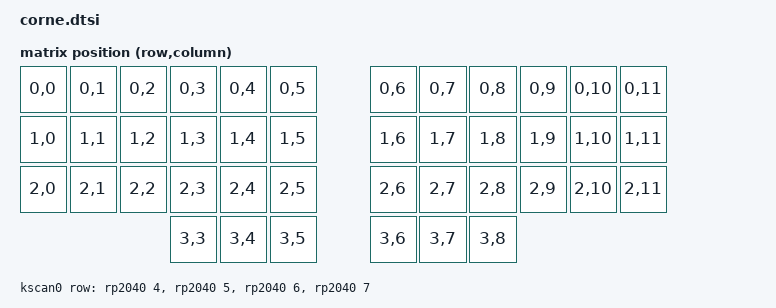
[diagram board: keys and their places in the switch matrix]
/*
 * Copyright (c) 2020 Pete Johanson
 *
 * SPDX-License-Identifier: MIT
 */
#include <dt-bindings/led/led.h>
#include <dt-bindings/zmk/matrix_transform.h>
#include "corne-layouts.dtsi"
/ {
	chosen {
		zephyr,display = &oled;
		zmk,kscan = &kscan0;
		zmk,physical-layout = &layout_0;
	};

	default_transform: keymap_transform_0 {
		compatible = "zmk,matrix-transform";
		columns = <12>;
		rows = <4>;
// | SW1  | SW2  | SW3  | SW4  | SW5  | SW6  |   | SW6  | SW5  | SW4  | SW3  | SW2  | SW1  |
// | SW7  | SW8  | SW9  | SW10 | SW11 | SW12 |   | SW12 | SW11 | SW10 | SW9  | SW8  | SW7  |
// | SW13 | SW14 | SW15 | SW16 | SW17 | SW18 |   | SW18 | SW17 | SW16 | SW15 | SW14 | SW13 |
//                      | SW19 | SW20 | SW21 |   | SW21 | SW20 | SW19 |
		map = <
RC(0,0) RC(0,1) RC(0,2) RC(0,3) RC(0,4) RC(0,5)  RC(0,6)  RC(0,7) RC(0,8) RC(0,9) RC(0,10) RC(0,11)
RC(1,0) RC(1,1) RC(1,2) RC(1,3) RC(1,4) RC(1,5)  RC(1,6)  RC(1,7) RC(1,8) RC(1,9) RC(1,10) RC(1,11)
RC(2,0) RC(2,1) RC(2,2) RC(2,3) RC(2,4) RC(2,5)  RC(2,6)  RC(2,7) RC(2,8) RC(2,9) RC(2,10) RC(2,11)
                        RC(3,3) RC(3,4) RC(3,5)  RC(3,6) RC(3,7) RC(3,8)
		>;
	};

	 kscan0: kscan {
        compatible = "zmk,kscan-gpio-matrix";
        label = "KSCAN";

        wakeup-source;
        diode-direction = "col2row";
		/* Rows: originally defined for ProMicro/nRF (&pro_micro). For RP2040
		   we map to &rp2040 with the same numeric GPIO indices by default.
		   Adjust if your board uses different pin numbering. */
		row-gpios = <&rp2040 4 (GPIO_ACTIVE_HIGH | GPIO_PULL_DOWN)>
			, <&rp2040 5 (GPIO_ACTIVE_HIGH | GPIO_PULL_DOWN)>
			, <&rp2040 6 (GPIO_ACTIVE_HIGH | GPIO_PULL_DOWN)>
			, <&rp2040 7 (GPIO_ACTIVE_HIGH | GPIO_PULL_DOWN)>;
    };
};

/* I2C / pinctrl: the original file used NRF_PSEL macros which are nRF-specific
   and will break RP2040 builds. Commenting original nRF pinctrl entries and
   providing an RP2040-friendly example below. */

/*
&pinctrl {
       i2c0_default: i2c0_default {
               group1 {
                       psels = <NRF_PSEL(TWIM_SDA, 0, 17)>,
                               <NRF_PSEL(TWIM_SCL, 0, 20)>;
               };
       };

       i2c0_sleep: i2c0_sleep {
               group1 {
                       psels = <NRF_PSEL(TWIM_SDA, 0, 17)>,
                               <NRF_PSEL(TWIM_SCL, 0, 20)>;
                       low-power-enable;
               };
       };
};
*/

/* RP2040 example: enable i2c0 and attach ssd1306. Update SDA/SCL GPIO numbers
   to match your board (common examples: SDA=26, SCL=27 on some RP2040 boards). */
&i2c0 {
    status = "okay";

    oled: ssd1306@3c {
        compatible = "solomon,ssd1306fb";
        reg = <0x3c>;
        width = <128>;
        height = <32>;
    };
};

/* Original ProMicro/nRF I2C node commented for reference:
&pro_micro_i2c {
    status = "okay";

    oled: ssd1306@3c {
        compatible = "solomon,ssd1306fb";
        reg = <0x3c>;
        width = <128>;
        height = <32>;
        segment-offset = <0>;
        page-offset = <0>;
        display-offset = <0>;
        multiplex-ratio = <31>;
        segment-remap;
        com-invdir;
        com-sequential;
        inversion-on;
        prechargep = <0x22>;
    };
};
*/

/* SPI / WS2812: original file used Nordic SPIM and NRF_PSEL macros; comment
   out the nRF-specific config. On RP2040, WS2812 is commonly driven via PIO
   or a dedicated driver; adapt below as needed. */

/*
&pinctrl {
    spi3_default: spi3_default {
        group1 {
            psels = <NRF_PSEL(SPIM_MOSI, 0, 6)>;
        };
    };

    spi3_sleep: spi3_sleep {
        group1 {
            psels = <NRF_PSEL(SPIM_MOSI, 0, 6)>;
            low-power-enable;
		};
	};
};

&spi3 {
	compatible = "nordic,nrf-spim";
	status = "okay";

	pinctrl-0 = <&spi3_default>;
	pinctrl-1 = <&spi3_sleep>;
	pinctrl-names = "default", "sleep";

	led_strip: ws2812@0 {
		compatible = "worldsemi,ws2812-spi";
		label = "WS2812";

		/* SPI */
		reg = <0>; /* ignored, but necessary for SPI bindings */
		spi-max-frequency = <4000000>;

		/* WS2812 */
		chain-length = <27>; /* There are per-key RGB, but the first 6 are underglow */
		spi-one-frame = <0x70>;
		spi-zero-frame = <0x40>;
		color-mapping = <LED_COLOR_ID_GREEN LED_COLOR_ID_RED LED_COLOR_ID_BLUE>;
	};
};
*/

/* Example note: to enable underglow on RP2040, implement an RP2040-compatible
   led_strip node (PIO or other). For now, the chosen node remains unchanged
   but the original implementation is commented for safety. */

/ {
	chosen {
		zmk,underglow = &led_strip;
	};
};
